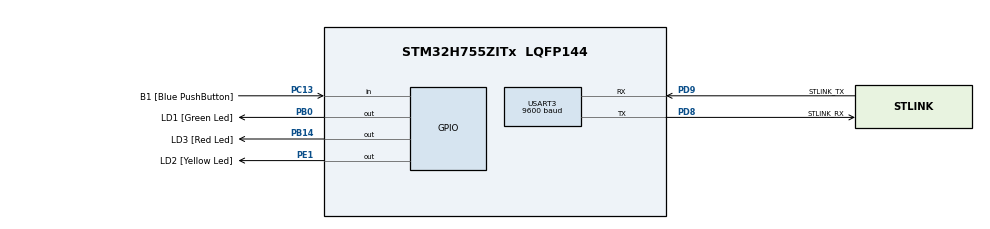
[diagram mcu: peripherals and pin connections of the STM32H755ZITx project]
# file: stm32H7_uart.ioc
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CORTEX_M7.default_mode_Activation=1
CortexM4.IPs=BDMA,CORTEX_M4\:I,DMA,FATFS_M4\:I,FREERTOS_M4\:I,GPIO,IWDG2\:I,MDMA,NVIC2\:I,OPENAMP_M4\:I,PDM2PCM_M4\:I,PWR,RCC,RESMGR_UTILITY,SYS_M4\:I,USB_DEVICE_M4\:I,USB_HOST_M4\:I,VREFBUF,WWDG2\:I,USART3
CortexM4.Pins=PE1
CortexM7.IPs=BDMA\:I,CORTEX_M7\:I,DMA\:I,FATFS_M7\:I,FREERTOS_M7\:I,GPIO\:I,IWDG1\:I,MDMA\:I,NVIC1\:I,OPENAMP_M7\:I,PDM2PCM_M7\:I,PWR\:I,RCC\:I,RESMGR_UTILITY\:I,SYS\:I,USB_DEVICE_M7\:I,USB_HOST_M7\:I,VREFBUF\:I,WWDG1\:I,USART3\:I,TIM13\:I
CortexM7.Pins=PC13,PB0,PB14
Mcu.Family=STM32H7
Mcu.Name=STM32H755ZITx
Mcu.Package=LQFP144
NVIC1.PriorityGroup=NVIC_PRIORITYGROUP_4
NVIC2.PriorityGroup=NVIC_PRIORITYGROUP_4
PB0.GPIO_Label=LD1 [Green Led]
PB0.PinAttribute=CortexM7
PB0.Signal=GPIO_Output
PB14.GPIO_Label=LD3 [Red Led]
PB14.PinAttribute=CortexM7
PB14.Signal=GPIO_Output
PC13.GPIO_Label=B1 [Blue PushButton]
PC13.PinAttribute=CortexM7
PC13.Signal=GPIO_Input
PC14-OSC32_IN\ (OSC32_IN).Mode=LSE-External-Oscillator
PC14-OSC32_IN\ (OSC32_IN).PinAttribute=Free
PC14-OSC32_IN\ (OSC32_IN).Signal=RCC_OSC32_IN
PC15-OSC32_OUT\ (OSC32_OUT).Mode=LSE-External-Oscillator
PC15-OSC32_OUT\ (OSC32_OUT).PinAttribute=Free
PC15-OSC32_OUT\ (OSC32_OUT).Signal=RCC_OSC32_OUT
PD8.GPIO_Label=STLINK_RX
PD8.Mode=Asynchronous
PD8.PinAttribute=CortexM7
PD8.Signal=USART3_TX
PD9.GPIO_Label=STLINK_TX
PD9.Mode=Asynchronous
PD9.PinAttribute=CortexM7
PD9.Signal=USART3_RX
PE1.GPIO_Label=LD2 [Yellow Led]
PE1.PinAttribute=CortexM4
PE1.Signal=GPIO_Output
PH0-OSC_IN\ (PH0).Mode=HSE-External-Clock-Source
PH0-OSC_IN\ (PH0).PinAttribute=Free
PH0-OSC_IN\ (PH0).Signal=RCC_OSC_IN
ProjectManager.HeapSize=M4-0x200,M7-0x200
ProjectManager.StackSize=M4-0x400,M7-0x400
ProjectManager.TargetToolchain=STM32CubeIDE
RCC.APB1Freq_Value=60000000
RCC.APB2Freq_Value=60000000
RCC.APB3Freq_Value=60000000
RCC.APB4Freq_Value=60000000
RCC.CortexFreq_Value=240000000
RCC.D2PPRE1=RCC_APB1_DIV2
RCC.DIVM1=1
RCC.DIVN1=60
RCC.HCLKFreq_Value=120000000
RCC.HPRE=RCC_HCLK_DIV2
RCC.HSE_VALUE=8000000
RCC.PLLFRACN=0
RCC.PLLSourceVirtual=RCC_PLLSOURCE_HSE
RCC.SYSCLKFreq_VALUE=240000000
RCC.SYSCLKSource=RCC_SYSCLKSOURCE_PLLCLK
RCC.USBFreq_Value=240000000
SYS.userName=SYS_M7
USART3.BaudRate=9600
USART3.VirtualMode-Asynchronous=VM_ASYNC
VP_SYS_M4_VS_Systick.Mode=SysTick
board=custom

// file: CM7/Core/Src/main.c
/* USER CODE BEGIN Header */
/**
  ******************************************************************************
  * @file           : main.c
  * @brief          : Main program body
  ******************************************************************************
  * @attention
  *
  * Copyright (c) 2024 STMicroelectronics.
  * All rights reserved.
  *
  * This software is licensed under terms that can be found in the LICENSE file
  * in the root directory of this software component.
  * If no LICENSE file comes with this software, it is provided AS-IS.
  *
  ******************************************************************************
  */
/* USER CODE END Header */
#include "main.h"

/* USER CODE BEGIN PD */

#ifndef HSEM_ID_0
#define HSEM_ID_0 (0U) /* HW semaphore 0*/
#endif

/* USER CODE END PD */

UART_HandleTypeDef huart3;

void SystemClock_Config(void);
static void MPU_Config(void);
static void MX_GPIO_Init(void);
static void MX_USART3_UART_Init(void);

/* USER CODE BEGIN 0 */
uint8_t tx_buffer = 'A';
uint8_t rx_buff;
/* USER CODE END 0 */

int main(void)
{

/* USER CODE BEGIN Boot_Mode_Sequence_0 */
  int32_t timeout;
/* USER CODE END Boot_Mode_Sequence_0 */

  /* MPU Configuration--------------------------------------------------------*/
  MPU_Config();

/* USER CODE BEGIN Boot_Mode_Sequence_1 */
  /* Wait until CPU2 boots and enters in stop mode or timeout*/
  timeout = 0xFFFF;
  while((__HAL_RCC_GET_FLAG(RCC_FLAG_D2CKRDY) != RESET) && (timeout-- > 0));
  if ( timeout < 0 )
  {
  Error_Handler();
  }
/* USER CODE END Boot_Mode_Sequence_1 */
  /* MCU Configuration--------------------------------------------------------*/

  /* Reset of all peripherals, Initializes the Flash interface and the Systick. */
  HAL_Init();

  /* Configure the system clock */
  SystemClock_Config();
/* USER CODE BEGIN Boot_Mode_Sequence_2 */
/* When system initialization is finished, Cortex-M7 will release Cortex-M4 by means of
HSEM notification */
/*HW semaphore Clock enable*/
__HAL_RCC_HSEM_CLK_ENABLE();
/*Take HSEM */
HAL_HSEM_FastTake(HSEM_ID_0);
/*Release HSEM in order to notify the CPU2(CM4)*/
HAL_HSEM_Release(HSEM_ID_0,0);
/* wait until CPU2 wakes up from stop mode */
timeout = 0xFFFF;
while((__HAL_RCC_GET_FLAG(RCC_FLAG_D2CKRDY) == RESET) && (timeout-- > 0));
if ( timeout < 0 )
{
Error_Handler();
}
/* USER CODE END Boot_Mode_Sequence_2 */

  /* Initialize all configured peripherals */
  MX_GPIO_Init();
  MX_USART3_UART_Init();

  /* Infinite loop */
  while (1)
  {

    /* USER CODE BEGIN 3 */
//	  HAL_UART_Transmit(&huart3, &tx_buffer, 10, 10);
//	  HAL_Delay(100);
//	  printf("A\n\r");
//	  HAL_Delay(100);

  }
  /* USER CODE END 3 */
}

void SystemClock_Config(void)
{
  RCC_OscInitTypeDef RCC_OscInitStruct = {0};
  RCC_ClkInitTypeDef RCC_ClkInitStruct = {0};

  /** Supply configuration update enable
  */
  HAL_PWREx_ConfigSupply(PWR_DIRECT_SMPS_SUPPLY);

  /** Configure the main internal regulator output voltage
  */
  __HAL_PWR_VOLTAGESCALING_CONFIG(PWR_REGULATOR_VOLTAGE_SCALE3);

  while(!__HAL_PWR_GET_FLAG(PWR_FLAG_VOSRDY)) {}

  /** Initializes the RCC Oscillators according to the specified parameters
  * in the RCC_OscInitTypeDef structure.
  */
  RCC_OscInitStruct.OscillatorType = RCC_OSCILLATORTYPE_HSE;
  RCC_OscInitStruct.HSEState = RCC_HSE_BYPASS;
  RCC_OscInitStruct.PLL.PLLState = RCC_PLL_ON;
  RCC_OscInitStruct.PLL.PLLSource = RCC_PLLSOURCE_HSE;
  RCC_OscInitStruct.PLL.PLLM = 2;
  RCC_OscInitStruct.PLL.PLLN = 37;
  RCC_OscInitStruct.PLL.PLLP = 2;
  RCC_OscInitStruct.PLL.PLLQ = 2;
  RCC_OscInitStruct.PLL.PLLR = 2;
  RCC_OscInitStruct.PLL.PLLRGE = RCC_PLL1VCIRANGE_2;
  RCC_OscInitStruct.PLL.PLLVCOSEL = RCC_PLL1VCOMEDIUM;
  RCC_OscInitStruct.PLL.PLLFRACN = 4096;
  if (HAL_RCC_OscConfig(&RCC_OscInitStruct) != HAL_OK)
  {
    Error_Handler();
  }

  /** Initializes the CPU, AHB and APB buses clocks
  */
  RCC_ClkInitStruct.ClockType = RCC_CLOCKTYPE_HCLK|RCC_CLOCKTYPE_SYSCLK
                              |RCC_CLOCKTYPE_PCLK1|RCC_CLOCKTYPE_PCLK2
                              |RCC_CLOCKTYPE_D3PCLK1|RCC_CLOCKTYPE_D1PCLK1;
  RCC_ClkInitStruct.SYSCLKSource = RCC_SYSCLKSOURCE_PLLCLK;
  RCC_ClkInitStruct.SYSCLKDivider = RCC_SYSCLK_DIV1;
  RCC_ClkInitStruct.AHBCLKDivider = RCC_HCLK_DIV2;
  RCC_ClkInitStruct.APB3CLKDivider = RCC_APB3_DIV2;
  RCC_ClkInitStruct.APB1CLKDivider = RCC_APB1_DIV2;
  RCC_ClkInitStruct.APB2CLKDivider = RCC_APB2_DIV2;
  RCC_ClkInitStruct.APB4CLKDivider = RCC_APB4_DIV2;

  if (HAL_RCC_ClockConfig(&RCC_ClkInitStruct, FLASH_LATENCY_0) != HAL_OK)
  {
    Error_Handler();
  }
}

static void MX_USART3_UART_Init(void)
{

  huart3.Instance = USART3;
  huart3.Init.BaudRate = 9600;
  huart3.Init.WordLength = UART_WORDLENGTH_8B;
  huart3.Init.StopBits = UART_STOPBITS_1;
  huart3.Init.Parity = UART_PARITY_NONE;
  huart3.Init.Mode = UART_MODE_TX_RX;
  huart3.Init.HwFlowCtl = UART_HWCONTROL_NONE;
  huart3.Init.OverSampling = UART_OVERSAMPLING_16;
  huart3.Init.OneBitSampling = UART_ONE_BIT_SAMPLE_DISABLE;
  huart3.Init.ClockPrescaler = UART_PRESCALER_DIV1;
  huart3.AdvancedInit.AdvFeatureInit = UART_ADVFEATURE_NO_INIT;
  if (HAL_UART_Init(&huart3) != HAL_OK)
  {
    Error_Handler();
  }
  if (HAL_UARTEx_SetTxFifoThreshold(&huart3, UART_TXFIFO_THRESHOLD_1_8) != HAL_OK)
  {
    Error_Handler();
  }
  if (HAL_UARTEx_SetRxFifoThreshold(&huart3, UART_RXFIFO_THRESHOLD_1_8) != HAL_OK)
  {
    Error_Handler();
  }
  if (HAL_UARTEx_DisableFifoMode(&huart3) != HAL_OK)
  {
    Error_Handler();
  }

}

static void MX_GPIO_Init(void)
{
  GPIO_InitTypeDef GPIO_InitStruct = {0};

  /* GPIO Ports Clock Enable */
  __HAL_RCC_GPIOC_CLK_ENABLE();
  __HAL_RCC_GPIOB_CLK_ENABLE();
  __HAL_RCC_GPIOD_CLK_ENABLE();

  /*Configure GPIO pin Output Level */
  HAL_GPIO_WritePin(GPIOB, LD1_Pin|LD3_Pin, GPIO_PIN_RESET);

  /*Configure GPIO pin : B1_Pin */
  GPIO_InitStruct.Pin = B1_Pin;
  GPIO_InitStruct.Mode = GPIO_MODE_INPUT;
  GPIO_InitStruct.Pull = GPIO_NOPULL;
  HAL_GPIO_Init(B1_GPIO_Port, &GPIO_InitStruct);

  /*Configure GPIO pins : LD1_Pin LD3_Pin */
  GPIO_InitStruct.Pin = LD1_Pin|LD3_Pin;
  GPIO_InitStruct.Mode = GPIO_MODE_OUTPUT_PP;
  GPIO_InitStruct.Pull = GPIO_NOPULL;
  GPIO_InitStruct.Speed = GPIO_SPEED_FREQ_LOW;
  HAL_GPIO_Init(GPIOB, &GPIO_InitStruct);

}

 /* MPU Configuration */

void MPU_Config(void)
{
  MPU_Region_InitTypeDef MPU_InitStruct = {0};

  /* Disables the MPU */
  HAL_MPU_Disable();

  /** Initializes and configures the Region and the memory to be protected
  */
  MPU_InitStruct.Enable = MPU_REGION_ENABLE;
  MPU_InitStruct.Number = MPU_REGION_NUMBER0;
  MPU_InitStruct.BaseAddress = 0x0;
  MPU_InitStruct.Size = MPU_REGION_SIZE_4GB;
  MPU_InitStruct.SubRegionDisable = 0x87;
  MPU_InitStruct.TypeExtField = MPU_TEX_LEVEL0;
  MPU_InitStruct.AccessPermission = MPU_REGION_NO_ACCESS;
  MPU_InitStruct.DisableExec = MPU_INSTRUCTION_ACCESS_DISABLE;
  MPU_InitStruct.IsShareable = MPU_ACCESS_SHAREABLE;
  MPU_InitStruct.IsCacheable = MPU_ACCESS_NOT_CACHEABLE;
  MPU_InitStruct.IsBufferable = MPU_ACCESS_NOT_BUFFERABLE;

  HAL_MPU_ConfigRegion(&MPU_InitStruct);
  /* Enables the MPU */
  HAL_MPU_Enable(MPU_PRIVILEGED_DEFAULT);

}

void Error_Handler(void)
{
  __disable_irq();
  while (1)
  {
  }
}
